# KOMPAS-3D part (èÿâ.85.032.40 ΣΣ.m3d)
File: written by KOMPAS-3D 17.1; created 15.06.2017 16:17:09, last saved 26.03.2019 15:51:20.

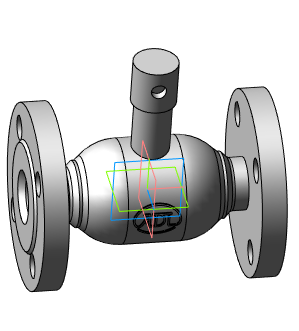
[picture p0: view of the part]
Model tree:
1. Операция без истории:2  (labels: Сталь 20  ГОСТ 1050-88)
